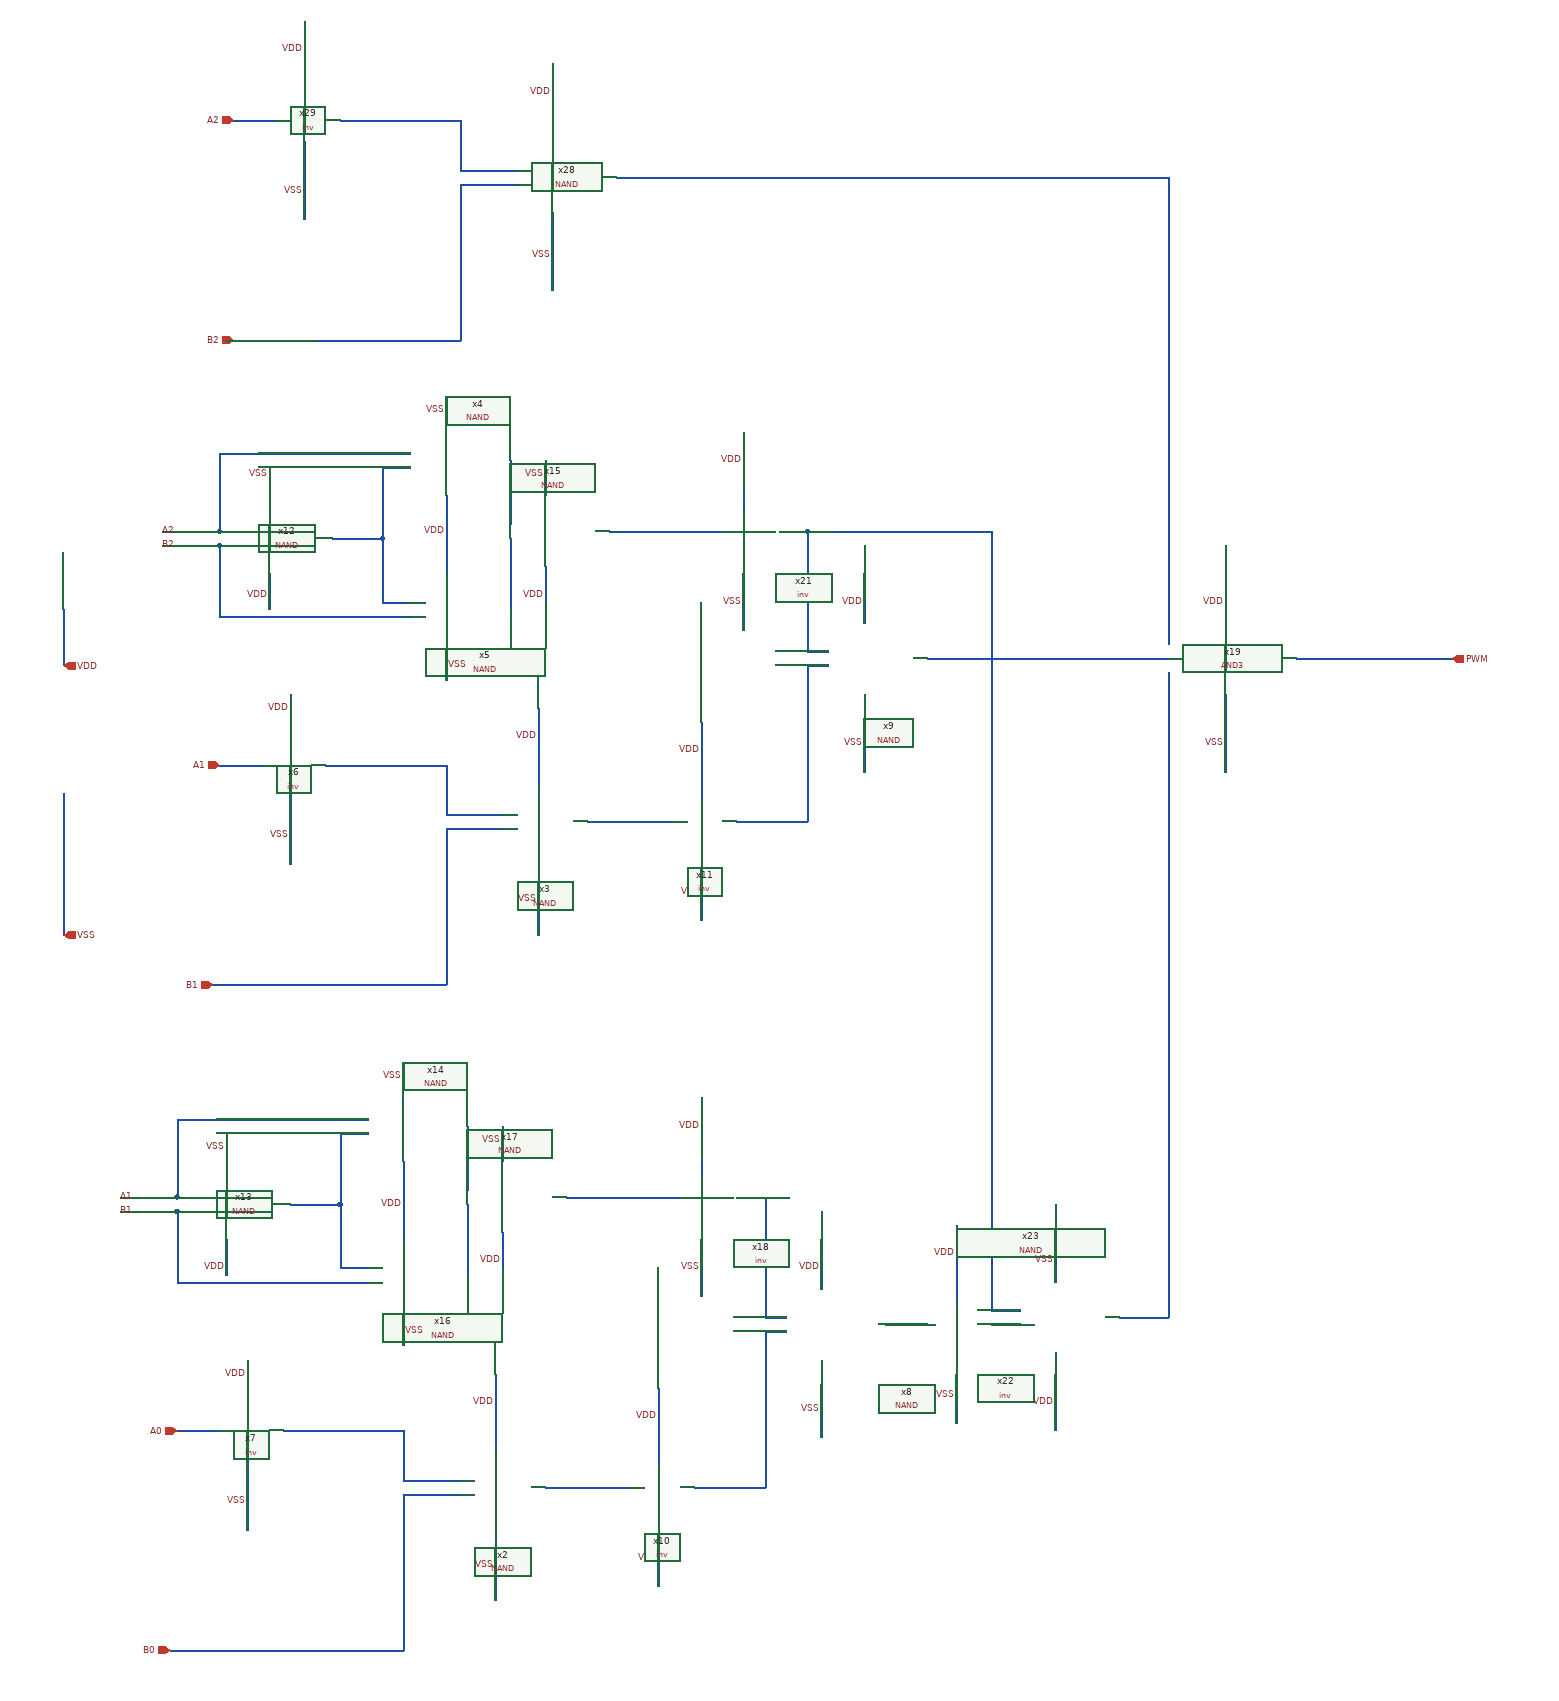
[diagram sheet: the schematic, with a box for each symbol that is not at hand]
v {xschem version=3.4.6 file_version=1.2}
G {}
K {}
V {}
S {}
E {}
N 1270 -3310 1270 -3230 {lab=VDD}
N 1270 -3050 1270 -2850 {lab=VSS}
N 1510 -4000 1570 -4000 {lab=A2}
N 1960 -4080 1960 -3970 {lab=VDD}
N 1960 -3870 1960 -3760 {lab=VSS}
N 1830 -3910 1830 -3690 {lab=B2}
N 1830 -3910 1910 -3910 {lab=B2}
N 1610 -3970 1610 -3860 {lab=VSS}
N 1610 -4140 1610 -4030 {lab=VDD}
N 1830 -4000 1830 -3930 {lab=#net1}
N 1660 -4000 1830 -4000 {lab=#net1}
N 1830 -3930 1910 -3930 {lab=#net1}
N 1500 -3690 1830 -3690 {lab=B2}
N 1490 -3090 1550 -3090 {lab=A1}
N 1940 -3170 1940 -3060 {lab=VDD}
N 1940 -2960 1940 -2850 {lab=VSS}
N 1810 -3000 1810 -2780 {lab=B1}
N 1810 -3000 1890 -3000 {lab=B1}
N 1590 -3060 1590 -2950 {lab=VSS}
N 1810 -3090 1810 -3020 {lab=#net2}
N 1640 -3090 1810 -3090 {lab=#net2}
N 1810 -3020 1890 -3020 {lab=#net2}
N 1480 -2780 1810 -2780 {lab=B1}
N 2910 -3190 2910 -3080 {lab=VSS}
N 2910 -3400 2910 -3290 {lab=VDD}
N 3010 -3240 3230 -3240 {lab=PWM}
N 2010 -3010 2130 -3010 {lab=#net3}
N 2170 -2980 2170 -2870 {lab=VSS}
N 2170 -3150 2170 -3040 {lab=VDD}
N 2490 -3240 2830 -3240 {lab=#net4}
N 2400 -3190 2400 -3080 {lab=VSS}
N 2400 -3400 2400 -3290 {lab=VDD}
N 1560 -3360 1560 -3310 {lab=VDD}
N 1650 -3410 1720 -3410 {lab=#net5}
N 1590 -3190 1590 -3120 {lab=VDD}
N 2050 -3920 2830 -3920 {lab=#net6}
N 1490 -3420 1510 -3420 {lab=A2}
N 1490 -3400 1510 -3400 {lab=B2}
N 1720 -3510 1760 -3510 {lab=#net5}
N 1720 -3510 1720 -3410 {lab=#net5}
N 1720 -3410 1720 -3320 {lab=#net5}
N 1720 -3320 1760 -3320 {lab=#net5}
N 1560 -3510 1560 -3460 {lab=VSS}
N 1490 -3530 1760 -3530 {lab=A2}
N 1490 -3530 1490 -3420 {lab=A2}
N 1410 -3420 1490 -3420 {lab=A2}
N 1490 -3300 1760 -3300 {lab=B2}
N 1490 -3400 1490 -3300 {lab=B2}
N 1410 -3400 1490 -3400 {lab=B2}
N 1810 -3260 1810 -3210 {lab=VSS}
N 1950 -3520 1950 -3470 {lab=VSS}
N 1950 -3370 1950 -3320 {lab=VDD}
N 1900 -3520 1900 -3430 {lab=#net7}
N 1900 -3410 1900 -3310 {lab=#net8}
N 2040 -3420 2200 -3420 {lab=#net9}
N 2230 -3390 2230 -3280 {lab=VSS}
N 2230 -3560 2230 -3450 {lab=VDD}
N 2280 -3420 2320 -3420 {lab=#net10}
N 2320 -3420 2320 -3250 {lab=#net10}
N 2320 -3250 2350 -3250 {lab=#net10}
N 2320 -3230 2350 -3230 {lab=#net11}
N 2320 -3230 2320 -3010 {lab=#net11}
N 2220 -3010 2320 -3010 {lab=#net11}
N 1430 -2150 1490 -2150 {lab=A0}
N 1880 -2230 1880 -2120 {lab=VDD}
N 1880 -2020 1880 -1910 {lab=VSS}
N 1750 -2060 1750 -1840 {lab=B0}
N 1750 -2060 1830 -2060 {lab=B0}
N 1530 -2120 1530 -2010 {lab=VSS}
N 1750 -2150 1750 -2080 {lab=#net12}
N 1580 -2150 1750 -2150 {lab=#net12}
N 1750 -2080 1830 -2080 {lab=#net12}
N 1420 -1840 1750 -1840 {lab=B0}
N 1950 -2070 2070 -2070 {lab=#net13}
N 2110 -2040 2110 -1930 {lab=VSS}
N 2110 -2210 2110 -2100 {lab=VDD}
N 2340 -2250 2340 -2140 {lab=VSS}
N 2340 -2460 2340 -2350 {lab=VDD}
N 1500 -2570 1500 -2520 {lab=VSS}
N 1590 -2470 1660 -2470 {lab=#net14}
N 1530 -2250 1530 -2180 {lab=VDD}
N 1430 -2480 1450 -2480 {lab=A1}
N 1430 -2460 1450 -2460 {lab=B1}
N 1750 -2670 1750 -2630 {lab=VSS}
N 1750 -2530 1750 -2420 {lab=VDD}
N 1660 -2570 1700 -2570 {lab=#net14}
N 1660 -2570 1660 -2470 {lab=#net14}
N 1660 -2470 1660 -2380 {lab=#net14}
N 1660 -2380 1700 -2380 {lab=#net14}
N 1500 -2420 1500 -2370 {lab=VDD}
N 1430 -2590 1700 -2590 {lab=A1}
N 1430 -2590 1430 -2480 {lab=A1}
N 1350 -2480 1430 -2480 {lab=A1}
N 1430 -2360 1700 -2360 {lab=B1}
N 1430 -2460 1430 -2360 {lab=B1}
N 1350 -2460 1430 -2460 {lab=B1}
N 1750 -2320 1750 -2270 {lab=VSS}
N 1890 -2580 1890 -2530 {lab=VSS}
N 1890 -2430 1890 -2380 {lab=VDD}
N 1840 -2580 1840 -2490 {lab=#net15}
N 1840 -2470 1840 -2370 {lab=#net16}
N 1980 -2480 2140 -2480 {lab=#net17}
N 2170 -2450 2170 -2340 {lab=VSS}
N 2170 -2620 2170 -2510 {lab=VDD}
N 2220 -2480 2260 -2480 {lab=#net18}
N 2260 -2480 2260 -2310 {lab=#net18}
N 2260 -2310 2290 -2310 {lab=#net18}
N 2260 -2290 2290 -2290 {lab=#net19}
N 2260 -2290 2260 -2070 {lab=#net19}
N 2160 -2070 2260 -2070 {lab=#net19}
N 2830 -3920 2830 -3260 {lab=#net6}
N 2530 -2270 2530 -2160 {lab=VSS}
N 2530 -2440 2530 -2330 {lab=VDD}
N 2430 -2300 2490 -2300 {lab=#net20}
N 2670 -2260 2670 -2150 {lab=VDD}
N 2670 -2470 2670 -2360 {lab=VSS}
N 2580 -2300 2620 -2300 {lab=#net21}
N 2760 -2310 2830 -2310 {lab=#net22}
N 2830 -3220 2830 -2310 {lab=#net22}
N 2320 -3420 2580 -3420 {lab=#net10}
N 2580 -3420 2580 -2320 {lab=#net10}
N 2580 -2320 2620 -2320 {lab=#net10}
N 1810 -3470 1810 -3360 {lab=VDD}
N 1810 -3610 1810 -3570 {lab=VSS}
C {iopin.sym} 1270 -3230 0 1 {name=p92 lab=VDD}
C {iopin.sym} 1270 -2850 0 1 {name=p93 lab=VSS}
C {ipin.sym} 1510 -4000 0 0 {name=p94 lab=A2}
C {lab_wire.sym} 1960 -4040 0 0 {name=p105 sig_type=std_logic lab=VDD}
C {NAND.sym} 2030 -3830 0 0 {name=x28}
C {lab_wire.sym} 1610 -3900 0 0 {name=p106 sig_type=std_logic lab=VSS
}
C {lab_wire.sym} 1610 -4100 0 0 {name=p107 sig_type=std_logic lab=VDD}
C {inv.sym} 1650 -3910 0 0 {name=x29}
C {lab_wire.sym} 1940 -3130 0 0 {name=p8 sig_type=std_logic lab=VDD}
C {NAND.sym} 2010 -2920 0 0 {name=x3}
C {lab_wire.sym} 1590 -2990 0 0 {name=p9 sig_type=std_logic lab=VSS
}
C {lab_wire.sym} 1590 -3170 0 0 {name=p10 sig_type=std_logic lab=VDD}
C {lab_wire.sym} 1960 -3810 0 0 {name=p1 sig_type=std_logic lab=VSS
}
C {lab_wire.sym} 1940 -2900 0 0 {name=p3 sig_type=std_logic lab=VSS
}
C {ipin.sym} 1510 -3690 0 0 {name=p17 lab=B2}
C {ipin.sym} 1490 -3090 0 0 {name=p19 lab=A1}
C {ipin.sym} 1480 -2780 0 0 {name=p23 lab=B1}
C {inv.sym} 1630 -3000 0 0 {name=x6}
C {NAND.sym} 2470 -3150 0 0 {name=x9}
C {lab_wire.sym} 2170 -2910 0 0 {name=p28 sig_type=std_logic lab=VSS
}
C {lab_wire.sym} 2170 -3110 0 0 {name=p29 sig_type=std_logic lab=VDD}
C {inv.sym} 2210 -2920 0 0 {name=x11}
C {lab_wire.sym} 2400 -3120 0 0 {name=p34 sig_type=std_logic lab=VSS}
C {lab_wire.sym} 2400 -3320 0 0 {name=p35 sig_type=std_logic lab=VDD
}
C {NAND.sym} 1630 -3500 2 1 {name=x12}
C {lab_wire.sym} 1560 -3330 2 1 {name=p58 sig_type=std_logic lab=VDD}
C {lab_wire.sym} 1560 -3500 2 1 {name=p59 sig_type=std_logic lab=VSS
}
C {lab_wire.sym} 1430 -3420 0 0 {name=p24 sig_type=std_logic lab=A2}
C {lab_wire.sym} 1430 -3400 0 0 {name=p12 sig_type=std_logic lab=B2}
C {NAND.sym} 1880 -3610 2 1 {name=x4}
C {NAND.sym} 1880 -3220 0 0 {name=x5}
C {lab_wire.sym} 1810 -3230 0 1 {name=p15 sig_type=std_logic lab=VSS}
C {NAND.sym} 2020 -3510 2 1 {name=x15}
C {lab_wire.sym} 1950 -3500 0 0 {name=p39 sig_type=std_logic lab=VSS}
C {lab_wire.sym} 1950 -3330 0 0 {name=p40 sig_type=std_logic lab=VDD
}
C {lab_wire.sym} 2230 -3320 0 0 {name=p2 sig_type=std_logic lab=VSS
}
C {lab_wire.sym} 2230 -3520 0 0 {name=p41 sig_type=std_logic lab=VDD}
C {inv.sym} 2270 -3330 0 0 {name=x21}
C {lab_wire.sym} 1880 -2190 0 0 {name=p4 sig_type=std_logic lab=VDD}
C {NAND.sym} 1950 -1980 0 0 {name=x2}
C {lab_wire.sym} 1530 -2050 0 0 {name=p5 sig_type=std_logic lab=VSS
}
C {lab_wire.sym} 1530 -2230 0 0 {name=p6 sig_type=std_logic lab=VDD}
C {lab_wire.sym} 1880 -1960 0 0 {name=p11 sig_type=std_logic lab=VSS
}
C {ipin.sym} 1430 -2150 0 0 {name=p18 lab=A0}
C {ipin.sym} 1420 -1840 0 0 {name=p20 lab=B0}
C {inv.sym} 1570 -2060 0 0 {name=x7}
C {NAND.sym} 2410 -2210 0 0 {name=x8}
C {lab_wire.sym} 2110 -1970 0 0 {name=p21 sig_type=std_logic lab=VSS
}
C {lab_wire.sym} 2110 -2170 0 0 {name=p22 sig_type=std_logic lab=VDD}
C {inv.sym} 2150 -1980 0 0 {name=x10}
C {lab_wire.sym} 2340 -2180 0 0 {name=p25 sig_type=std_logic lab=VSS}
C {lab_wire.sym} 2340 -2380 0 0 {name=p26 sig_type=std_logic lab=VDD
}
C {NAND.sym} 1570 -2560 2 1 {name=x13}
C {lab_wire.sym} 1500 -2550 0 0 {name=p33 sig_type=std_logic lab=VSS}
C {lab_wire.sym} 1500 -2380 0 0 {name=p36 sig_type=std_logic lab=VDD}
C {lab_wire.sym} 1370 -2480 0 0 {name=p37 sig_type=std_logic lab=A1}
C {lab_wire.sym} 1370 -2460 0 0 {name=p42 sig_type=std_logic lab=B1}
C {NAND.sym} 1820 -2670 2 1 {name=x14}
C {lab_wire.sym} 1750 -2650 0 0 {name=p43 sig_type=std_logic lab=VSS}
C {lab_wire.sym} 1750 -2470 0 0 {name=p44 sig_type=std_logic lab=VDD
}
C {NAND.sym} 1820 -2280 0 0 {name=x16}
C {lab_wire.sym} 1750 -2290 0 1 {name=p45 sig_type=std_logic lab=VSS}
C {NAND.sym} 1960 -2570 2 1 {name=x17}
C {lab_wire.sym} 1890 -2560 0 0 {name=p46 sig_type=std_logic lab=VSS}
C {lab_wire.sym} 1890 -2390 0 0 {name=p47 sig_type=std_logic lab=VDD
}
C {lab_wire.sym} 2170 -2380 0 0 {name=p48 sig_type=std_logic lab=VSS
}
C {lab_wire.sym} 2170 -2580 0 0 {name=p49 sig_type=std_logic lab=VDD}
C {inv.sym} 2210 -2390 0 0 {name=x18}
C {AND3.sym} 2910 -3240 0 0 {name=x19}
C {lab_wire.sym} 2910 -3120 0 0 {name=p50 sig_type=std_logic lab=VSS}
C {lab_wire.sym} 2910 -3320 0 0 {name=p51 sig_type=std_logic lab=VDD
}
C {opin.sym} 3230 -3240 0 0 {name=p52 lab=PWM}
C {lab_wire.sym} 2530 -2200 0 0 {name=p53 sig_type=std_logic lab=VSS
}
C {lab_wire.sym} 2530 -2400 0 0 {name=p54 sig_type=std_logic lab=VDD}
C {inv.sym} 2570 -2210 0 0 {name=x22}
C {NAND.sym} 2740 -2400 2 1 {name=x23}
C {lab_wire.sym} 2670 -2190 0 0 {name=p55 sig_type=std_logic lab=VDD}
C {lab_wire.sym} 2670 -2390 0 0 {name=p56 sig_type=std_logic lab=VSS
}
C {lab_wire.sym} 1810 -3420 0 0 {name=p7 sig_type=std_logic lab=VDD}
C {lab_wire.sym} 1810 -3590 0 0 {name=p13 sig_type=std_logic lab=VSS
}
